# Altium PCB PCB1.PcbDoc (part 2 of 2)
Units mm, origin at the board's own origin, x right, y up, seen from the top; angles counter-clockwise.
Board outline 125 x 85 mm, 2 copper layers (Top Layer, Bottom Layer), stack 1.671 mm thick; 127 components, 99 nets, 530 pads, 139 vias.

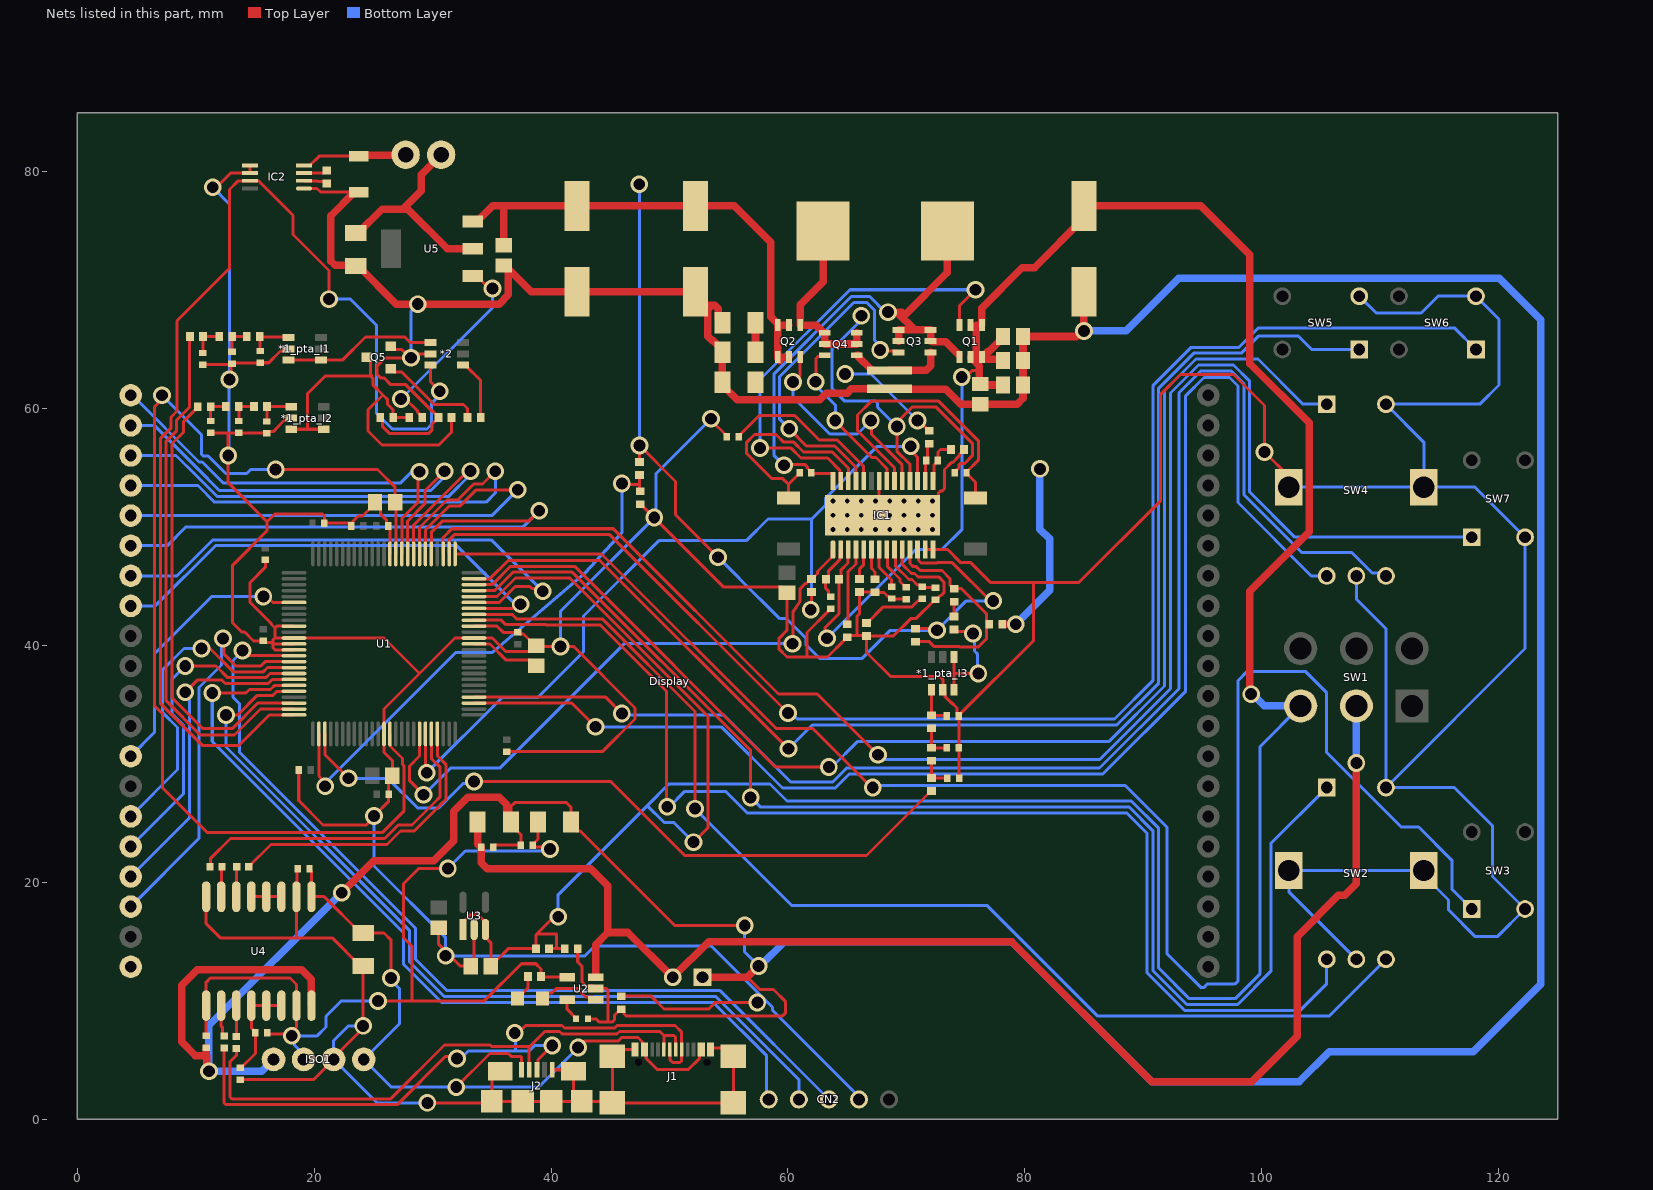
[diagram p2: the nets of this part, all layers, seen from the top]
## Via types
v1: diameter 1.5, hole 1, Top Layer to Bottom Layer, 111 vias
v2: diameter 0.5, hole 0.4, Top Layer to Bottom Layer, 12 vias
v3: diameter 0.5, hole 0.4, Top Layer to Bottom Layer, tented top, 6 vias
v4: diameter 0.5, hole 0.4, Top Layer to Bottom Layer, tented both sides, 6 vias
v5: diameter 3.5, hole 3, Top Layer to Bottom Layer, 4 vias

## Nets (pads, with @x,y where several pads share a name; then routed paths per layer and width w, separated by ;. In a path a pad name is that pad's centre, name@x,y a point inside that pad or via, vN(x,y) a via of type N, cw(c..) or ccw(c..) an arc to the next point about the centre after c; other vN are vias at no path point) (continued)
GND: *1_pta_I1.2 *1_pta_I2.2 *1_pta_I3.2 C1.1 C2.1 C3.1 C4.1 C5.1 C6.1 C7.1 C8.1 C9.1 C10.1 C11.1 C12.1 C27.2 C30.1 C31.1 C34.1 C35.1 C36.2 C37.1 C38.1 C39_pta_I1.1 C39_pta_I2.1 C39_pta_I3.1 C40_pta_I1.1 C40_pta_I2.1 C40_pta_I3.1 C41_pta_I1.1 C41_pta_I2.1 C41_pta_I3.1 CN2.4 Display.21 IC1.10 IC1.13 IC1.14 IC2.5 IC2.6 R8.1 R10.1 R14.1 R18.1 R19.2 R30.1 SW2.2 SW2.4 SW2.6 SW2.7 SW3.3 SW4.2 SW4.4 SW4.6 SW4.7 SW5.3 SW6.3 SW7.3 U1.10 U1.12 U1.13 U1.14 U1.38 U1.64 U1.66 U1.87 U3.2 | length 576.4
  Top Layer w0.254: C39_pta_I1.1@10.575,63.7 10.625,63.75 C40_pta_I1.1@13,63.75 ; C39_pta_I2.1@11.249,57.963 12.73,57.963 ; v1(11.425,78.697) 11.744,78.697 12.944,79.897 IC2.6@14.577,79.897 IC2.5@14.577,80.547 ; v1(12.85,62.465) 12.95,62.565 12.95,63.7 C40_pta_I1.1@13,63.75 ; C8.1@15.867,47.228 15.867,46.599 14.579,45.311 14.579,43.649 16.393,41.836 16.393,41.779 16.684,41.488 ; *1_pta_I1.2@17.814,65.05 17.641,64.877 17.153,64.877 16.155,63.879 15.459,63.879 C41_pta_I1.1@15.454,63.875 15.417,63.838 13.088,63.838 C40_pta_I1.1@13.05,63.8 C40_pta_I1.1@13,63.75 ; *1_pta_I2.2@18.05,59.214 17.877,59.041 17.488,59.041 16.739,58.291 16.739,58.263 16.535,58.059 16.122,58.059 C41_pta_I2.1@15.979,57.916 15.956,57.94 13.649,57.94 C40_pta_I2.1@13.625,57.963 12.73,57.963 ; U1.14@18.289,39.636 16.684,39.636 16.535,39.785 16.535,40.136 ; U1.13@18.289,40.136 16.535,40.136 ; U1.10@18.289,41.636 16.832,41.636 16.684,41.488 ; C6.1@18.689,29.487 18.689,26.907 20.745,24.852 24.393,24.852 25.039,25.497 v1(25.039,25.595) 26.283,26.839 C7.1@26.283,27.436 26.283,28.694 C1.1@26.589,29 26.589,30.286 25.889,30.986 U1.38@25.889,32.536 25.889,34.643 28.886,37.639 ; C10.1@23.122,50.092 C10.1@23.122,50.342 ; C2.1@26.239,50.092 26.116,50.215 26.116,50.59 25.609,51.097 25.609,51.635 C12.1@25.136,52.108 25.136,52.008 24.067,50.938 23.718,50.938 C10.1@23.122,50.342 ; C2.1@26.29,50.092 26.38,50.092 26.38,48.658 26.389,48.649 U1.87@26.389,47.736 ; C38.1@30.5,16.165 30.5,14.776 v1@31.428,13.848 ; v1(31.095,13.796) 31.375,13.796 v1@31.428,13.848 ; U1.66@33.489,41.636 35.437,41.637 35.957,41.117 C5.1@37.176,41.117 ; U3.2@33.5,16.015 33.5,13.216 C37.1@33.205,12.921 32.355,12.921 v1@31.428,13.848 ; C3.1@36.243,31.03 44.319,31.03 47.093,33.804 47.093,34.731 41.897,39.927 v1(40.8,39.927) C11.1@38.812,39.927 ; C5.1@37.275,41.068 37.369,40.974 37.665,40.974 C11.1@38.652,39.987 ; C11.1@38.752,39.987 C11.1@38.652,39.987 ; R19.2@45.923,10.384 48.457,10.384 49.528,9.313 53.319,9.313 53.856,9.849 v1(57.418,9.849) ; R30.1@47.524,51.933 47.574,51.933 v1(48.706,50.8) 54.583,44.923 59.444,44.923 C36.2@59.917,44.45 59.917,41.283 59.256,40.621 59.256,39.685 59.918,39.022 61.61,39.022 ; v1(53.51,59.153) 53.51,59.03 54.845,57.696 C31.1@54.845,57.646 ; C27.2@63.6,43.106 63.55,43.106 63.407,42.963 63.407,42.9 61.61,41.103 61.61,39.022 ; IC1.10@69.65,48.1 69.65,46.862 70.433,46.079 70.695,46.079 70.974,45.8 72.725,45.8 73.164,45.361 73.164,44.449 72.941,44.225 72.862,44.225 72.513,43.876 C35.1@72.463,43.876 72.413,43.876 70.804,42.267 70.367,42.267 68.9,40.8 R18.1@66.638,40.8 ; C30.1@69.993,43.92 69.965,43.948 68.791,43.948 C34.1@68.763,43.975 68.62,44.118 68.473,44.118 68.116,44.475 67.385,44.475 R10.1@67.36,44.5 67.348,44.513 66.069,44.513 R14.1@66.056,44.525 66.056,42.692 65.849,42.485 65.849,40.85 ; IC1.13@71.6,48.1 IC1.14@72.25,48.1 73.493,48.1 74.593,47 75.435,47 77.093,45.342 80.749,45.342 ; C41_pta_I3.1@74.425,34.05 C40_pta_I3.1@74.425,31.366 74.438,31.353 74.438,28.805 C39_pta_I3.1@74.451,28.791 ; SW4.6@101.277,51.954 102.3,52.977 SW4.6@102.3,53.377 102.3,54.302 v1(100.251,56.351) 100.251,60.267 97.623,62.895 93.143,62.895 91.475,61.226 91.475,52.236 84.581,45.342 80.749,45.342 ; 12.73,57.963 v1(12.73,56.05) 12.73,53.743 16.011,50.462 ; 16.011,50.462 16.011,49.684 13.111,46.783 13.111,41.898 13.866,41.142 14.117,41.142 14.873,40.387 C4.1@15.704,40.387 15.847,40.244 16.376,40.244 16.483,40.136 16.535,40.136 ; 16.011,50.462 16.651,51.102 20.7,51.102 20.849,50.953 C9.1@20.849,50.342 C10.1@23.122,50.342 ; 16.535,40.136 16.535,40.488 16.684,40.636 ; 16.684,40.636 U1.12@18.289,40.636 25.889,40.636 28.886,37.639 ; 16.684,40.636 16.684,41.488 ; 28.886,37.639 31.883,40.636 U1.64@33.489,40.636 35.036,40.636 36.194,39.478 38.144,39.478 C11.1@38.652,39.987 ; 61.61,39.022 63.347,39.022 64.765,40.44 64.765,40.49 64.836,40.561 64.886,40.561 R8.1@65.013,40.688 65.175,40.85 65.849,40.85 ; 65.849,40.85 66.588,40.85 R18.1@66.638,40.8 ; R18.1@66.638,40.8 66.638,39.415 68.655,37.398 72.818,37.398 73.075,37.142 *1_pta_I3.2@73.075,36.266 73.248,36.093 73.248,35.705 73.828,35.125 73.878,35.125 74.282,34.721 74.282,34.193 C41_pta_I3.1@74.425,34.05 74.425,34.1 80.749,40.424 80.749,45.342
  Bottom Layer w0.254: v1(11.425,78.697) 12.85,77.272 v1(12.85,62.465) 12.79,62.405 12.79,56.11 v1(12.73,56.05) ; v1(25.039,25.595) 25.039,21.377 31.095,15.321 v1(31.095,13.796) 42.859,13.796 43.683,14.62 53.526,14.62 v1@57.857,10.289 ; v1(40.8,39.927) 40.8,42.894 48.875,50.969 48.875,54.518 v1(53.51,59.153) ; v1(57.418,9.849) v1@57.857,10.289 ; CN2.4@66,1.665 66,1.906 58.695,9.211 58.695,9.451 v1@57.857,10.289 ; SW4.6@102.3,53.377 SW4.7@113.7,53.377 ; SW2.4@108,13.5 102.3,19.2 SW2.6@102.3,21 SW2.7@113.7,21 113.7,20.6 115.783,18.517 115.783,17.679 118.051,15.41 119.91,15.41 SW3.3@122.25,17.75 119.5,20.5 119.5,24.78 116.28,28 SW2.2@110.5,28 ; SW4.4@108,45.876 108,43.925 110.5,41.425 SW2.2@110.5,28 ; SW5.3@108.25,69.5 109.675,68.075 113.475,68.075 114.9,69.5 SW6.3@118.1,69.5 120.05,67.55 120.05,62 118.426,60.376 SW4.2@110.5,60.376 113.7,57.176 SW4.7@113.7,53.377 ; SW2.2@110.5,28 122.25,39.75 SW7.3@122.25,49.144 118.017,53.377 SW4.7@113.7,53.377
Net*1_pta_I1_1: *1_pta_I1.1 C41_pta_I1.2 R22_pta_I1.2 | length 3.7
  Top Layer w0.254: R22_pta_I1.2@15.404,66.1 R22_pta_I1.2@15.429,66.075 ; C41_pta_I1.2@15.454,64.875 15.429,64.9 R22_pta_I1.2@15.429,66.075 ; *1_pta_I1.1@17.814,66 17.764,66.05 15.454,66.05 R22_pta_I1.2@15.429,66.075
Net*1_pta_I1_3: *1_pta_I1.3 *1_pta_I1.4 *2.1 | length 13
  Top Layer w0.254: *1_pta_I1.3@17.814,64.1 *1_pta_I1.4@20.564,64.1 22.372,64.1 24.328,66.056 27.64,66.056 28.121,65.575 *2.1@29.804,65.575
Net*1_pta_I2_1: *1_pta_I2.1 C41_pta_I2.2 R22_pta_I2.2 | length 3.3
  Top Layer w0.254: C41_pta_I2.2@15.979,58.916 15.992,58.929 15.992,60.165 R22_pta_I2.2@16.004,60.177 16.011,60.17 18.043,60.17 *1_pta_I2.1@18.05,60.164
Net*1_pta_I2_3: *1_pta_I2.3 *1_pta_I2.4 Q5.3 R31.1 R32.2 R33.2 | length 32
  Top Layer w0.254: *1_pta_I2.3@18.05,58.263 19.425,58.263 ; *1_pta_I2.4@20.8,58.263 19.425,58.263 ; Q5.3@24.445,64.325 24.495,64.325 24.768,64.052 24.768,62.881 24.819,62.83 24.819,62.69 24.939,62.571 24.939,62.025 25.801,61.162 ; 24.819,62.765 20.925,62.765 19.425,61.265 19.425,58.263 ; R31.1@28.025,59.264 R32.2@26.664,59.264 26.664,59.887 26.199,60.351 26.199,60.764 25.801,61.162 ; R33.2@31.586,59.264 31.586,58 30.511,56.925 25.725,56.925 24.539,58.112 24.539,59.9 25.801,61.162
Net*1_pta_I3_1: *1_pta_I3.1 C41_pta_I3.2 R22_pta_I3.2 | length 3.5
  Top Layer w0.254: *1_pta_I3.1@72.125,36.266 R22_pta_I3.2@72.125,34.111 72.156,34.081 73.394,34.081 C41_pta_I3.2@73.425,34.05
Net*1_pta_I3_3: *1_pta_I3.3 *1_pta_I3.4 R16.2 | length 10.1
  Top Layer w0.254: R16.2@74.016,41.35 74.179,41.188 75.458,41.188 v1(75.62,41.025) ; *1_pta_I3.3@74.025,36.266 74.025,37.641 ; *1_pta_I3.4@74.025,39.016 74.025,37.641 ; v1(76.08,37.641) 74.025,37.641
  Bottom Layer w0.254: v1(75.62,41.025) 75.75,40.895 75.75,39.544 75.994,39.3 75.994,37.728 v1(76.08,37.641)
Net*2_3: *2.3 IC2.7 U1.25 | length 98.2
  Top Layer w0.254: U1.25@18.289,34.128 16.201,34.128 13.646,31.573 10.55,31.573 7,35.123 7,57.466 7.882,58.348 7.882,59.264 8.416,59.798 8.416,67.416 12.85,71.85 12.85,78.51 13.549,79.209 14.539,79.209 IC2.7@14.577,79.247 15.288,79.247 18.203,76.332 18.203,74.71 21.239,71.674 v1(21.239,69.25) ; *2.3@29.804,63.675 29.804,62.289 30.539,61.554 30.539,61.529 v1(30.591,61.477)
  Bottom Layer w0.254: v1(21.239,69.25) 23.05,69.25 25.239,67.061 25.239,59.639 26.586,58.291 29.526,58.291 29.913,58.678 29.913,60.462 30.539,61.088 30.539,61.425 v1(30.591,61.477)
Net*2_4: *2.4 R34.2 | length 5.1
  Top Layer w0.254: *2.4@32.554,63.675 32.754,63.675 34.047,62.381 R34.2@34.047,59.264
NetC11_2: C11.2 U1.63 | length 6
  Top Layer w0.254: U1.63@33.489,40.136 34.835,40.136 36.212,38.759 38.279,38.759 C11.2@38.752,38.286
NetC12_2: C12.2 U1.39 U1.86 | length 93.2
  Top Layer w0.254: v1(7.136,61.13) 7.136,60.794 6.505,60.162 6.505,34.918 7.2,34.223 7.2,27.969 10.974,24.195 25.739,24.195 27.557,26.013 27.557,29.853 27.455,29.955 27.455,30.464 26.398,31.52 26.398,32.528 U1.39@26.389,32.536 ; v1(16.739,54.862) 25.345,54.862 26.836,53.371 C12.2@26.836,52.108 26.889,52.055 U1.86@26.889,47.736
  Bottom Layer w0.254: v1(7.136,61.13) 10.474,57.793 10.474,56.149 10.623,56 11.036,56 12.518,54.518 14.288,54.518 14.632,54.862 v1(16.739,54.862)
NetC13_2: C13.2 C14.2 C45.2 C46.2 ISO1.3 R1.2 U2.4 U4.9 U4.15 | length 76.2
  Top Layer w0.254: C45.2@10.872,7.045 U4.9@10.872,9.59 10.872,11.567 11.222,11.917 17.943,11.917 18.492,11.369 U4.15@18.492,9.59 18.492,7.776 18.099,7.382 v1(18.099,7.045) 17.966,7.178 16.165,7.178 C46.2@16.032,7.311 ; v1(25.383,9.99) 28.239,9.99 ; v1(31.281,21.17) 31.261,21.15 28.8,21.15 27.539,19.89 27.539,15.332 28.239,14.632 28.239,9.99 ; C13.2@38.9,25.095 38.9,23.645 38.45,23.195 C14.2@38.45,23.145 38.45,23.128 38.593,22.985 39.74,22.985 v1(39.9,22.825) ; U2.4@41.354,11.981 41.327,12.008 39.179,12.008 R1.2@39.152,12.035 39.152,12.681 38.708,13.126 37.494,13.126 34.358,9.99 28.239,9.99
  Bottom Layer w0.254: ISO1.3@19.099,5.045 19.099,5.475 18.337,6.236 18.337,6.807 v1(18.099,7.045) 20.25,7.045 20.995,7.79 20.995,8.687 22.298,9.99 v1(25.383,9.99) ; v1(31.281,21.17) 32.761,22.65 39.725,22.65 v1(39.9,22.825)
NetC15_2: C15.2 C16.2 P1.2 SW1.2 U2.3 | length 121
  Top Layer w0.635: C15.2@33.8,25.095 33.8,23.225 34.055,22.97 C16.2@34.1,22.97 34.1,21.655 34.592,21.164 43.33,21.164 44.8,19.694 44.8,15.765 ; U2.3@43.754,11.981 43.754,14.719 44.8,15.765 ; v1(108,30.075) 108,19.89 107.01,18.9 106.49,18.9 103,15.41 103,7 99.165,3.165 90.714,3.165 78.879,15 53.294,15 P1.2@50.275,11.981 46.491,15.765 44.8,15.765
  Bottom Layer w0.635: v1(108,30.075) SW1.2@108,34.903
NetC17_1: C17.1 C23.2 C24.2 C25.2 C26.2 C37.2 IC1.3 Q1.2 R3.1 R3.2 R4.2 R6.2 SW1.3 U1.71 U3.1 U3.3 | length 292.5
  Top Layer w0.254: U3.1@32.55,16.015 32.55,16.611 32.813,16.874 32.813,16.896 33.215,17.298 33.785,17.298 34.45,16.633 U3.3@34.45,16.015 34.45,15.356 34.905,14.901 C37.2@34.905,13.021 ; U1.71@33.414,44.136 35.423,44.136 36.985,45.699 41.577,45.699 53.263,34.012 53.263,24.634 v1(52.025,23.395) ; C37.2@34.905,12.921 C37.2@34.905,13.021 ; R3.1@39.827,14.396 R4.2@41.15,14.396 ; 40.45,14.396 40.45,15.64 38.803,15.64 38.727,15.565 ; v1(40.6,17.09) 40.252,17.09 38.727,15.565 ; v1(63.292,40.608) 63.144,40.756 63.144,41.521 64.31,42.688 R6.2@64.31,45.6 64.463,45.753 64.463,46.356 65.076,46.969 65.076,48.076 IC1.3@65.1,48.1 ; v1(74.683,62.671) 75.02,62.671 75.587,63.239 75.863,63.239 76.175,62.926 ; C37.2@34.905,13.021 35.378,13.494 35.478,13.494 36.38,14.396 R3.2@38.727,14.396 38.727,15.565
  Top Layer w0.635: Q1.2@75.425,64.247 75.492,64.18 75.607,64.18 76.175,63.612 76.175,62.926 76.175,62.359 76.25,62.284 C23.2@76.25,62.076 ; Q1.2@75.425,64.362 75.9,64.362 ; C23.2@76.25,62 C24.2@78.15,62 ; Q1.2@76.375,64.169 78.05,64.169 C25.2@78.15,64.069 ; C26.2@78.15,66.096 78.15,65.996 76.969,64.815 76.828,64.815 Q1.2@76.375,64.362 75.9,64.362 ; v1(99.118,35.892) 99,36.011 99,44.586 104.022,49.608 104.022,58.793 99,63.815 99,73 94.875,77.125 C17.1@84.999,77.125 84.999,76.075 80.846,71.922 79.796,71.922 76.375,68.501 Q1.2@76.375,67.062 75.9,67.062 75.9,64.362
  Bottom Layer w0.254: v1(40.6,17.09) 40.6,18.956 48.124,26.48 ; v1(52.025,23.395) 50.363,25.057 49.547,25.057 48.124,26.48 ; v1(63.292,40.608) 70.784,48.1 73,48.1 74.683,49.783 v1(74.683,62.671) ; SW1.3@103.3,34.903 99.875,31.478 99.875,12.285 97.77,10.18 93.894,10.18 91.307,12.767 91.307,24.563 89,26.87 59.914,26.87 58.487,28.297 49.941,28.297 48.124,26.48
  Bottom Layer w0.635: v1(99.118,35.892) 99.234,35.892 100.224,34.903 SW1.3@103.3,34.903
NetC18_1: C18.1 C19.1 C20.2 C21.2 C22.2 C47.2 IC1.12 Q2.2 R13.2 R29.2 U5.3 | length 119.9
  Top Layer w0.254: R29.2@47.474,55.493 v1(47.474,56.884) 50.499,53.859 50.499,51.054 v1(54.103,47.45) ; R13.2@70.76,41.422 72.442,41.422 v1(72.58,41.284) ; IC1.12@70.95,48.1 71.019,48.031 71.019,47.192 71.242,46.969 72.608,46.969 72.639,47 73.875,47 77.103,43.772 v1(77.34,43.772)
  Top Layer w0.635: U5.3@33.386,75.8 33.736,75.8 35.061,77.125 36.1,77.125 ; C47.2@36,73.8 36,77.025 36.1,77.125 ; C21.2@57.26,64.762 C22.2@57.26,67.25 ; Q2.2@59.069,67.245 58.537,67.777 58.537,74.05 55.462,77.125 C19.1@52.199,77.125 C18.1@42.199,77.125 36.1,77.125 ; Q2.2@59.137,64.247 Q2.2@59.137,64.362 ; Q2.2@59.315,64.069 Q2.2@59.315,64.158 ; Q2.2@60.086,64.362 Q2.2@59.137,64.362 ; Q2.2@60.086,67.062 Q2.2@59.137,67.062 Q2.2@59.137,64.362
  Bottom Layer w0.254: v1(47.449,78.95) 47.461,78.938 47.461,56.897 v1(47.474,56.884) ; v1@54.15,47.403 57.636,43.917 57.665,43.917 59.313,42.269 59.87,42.269 61.518,40.621 61.518,40.064 62.662,38.92 66.27,38.92 68.634,41.284 v1(72.58,41.284) 75.067,43.772 v1(77.34,43.772)
NetC27_1: C27.1 IC1.2 R6.1 | length 4.7
  Top Layer w0.254: R6.1@63.21,45.6 R6.1@63.191,45.581 ; C27.1@63.6,44.106 63.55,44.106 63.407,44.249 63.407,44.629 63.191,44.844 R6.1@63.191,45.581 ; IC1.2@64.45,48.1 64.381,48.031 64.381,47.251 63.408,46.278 63.408,45.798 R6.1@63.191,45.581
NetC28_1: C28.1 IC1.28 L1.1 Q1.1 Q3.2 | length 46.5
  Top Layer w0.254: v1(59.665,55.223) 59.743,55.301 61.41,55.301 61.633,55.078 61.633,54.999 61.982,54.65 C28.1@61.982,54.6 ; C28.1@62.007,54.625 62.109,54.523 63.727,54.523 63.8,54.45 IC1.28@63.8,53.9
  Top Layer w0.635: Q3.2@69.347,65.712 Q3.2@69.347,66.662 70.697,66.662 ; L1.1@73.469,75 73.469,71.5 69.858,67.889 69.594,68.153 v1(68.453,68.153) 69.206,68.153 70.697,66.662 ; Q1.1@74.407,64.545 73.307,65.645 72.23,65.645 72.162,65.712 Q3.2@72.047,65.712 Q3.2@72.047,66.662 70.697,66.662
  Bottom Layer w0.254: v1(59.665,55.223) 58.811,56.077 58.811,62.919 65.356,69.465 66.904,69.465 68.216,68.153 v1(68.453,68.153)
NetC28_2: C28.2 D2.1 IC1.26 | length 19.2
  Top Layer w0.254: D2.1@60.048,52.45 60.048,53.616 ; C28.2@60.982,54.6 60.982,54.55 60.048,53.616 ; IC1.26@65.1,53.9 65.1,54.986 63.741,56.345 61.305,56.345 60.48,57.17 59.636,57.17 58.985,57.821 57.179,57.821 56.516,57.158 56.516,56.221 58.646,54.092 59.572,54.092 60.048,53.616
NetC29_1: C29.1 IC1.16 R9.1 | length 3.3
  Top Layer w0.254: IC1.16@71.6,53.9 71.6,55.559 71.798,55.758 71.798,56.897 R9.1@71.933,57.032
NetC29_2: C29.2 IC1.15 R12.1 | length 3.8
  Top Layer w0.254: IC1.15@72.25,53.9 72.314,53.964 72.314,55.223 72.663,55.572 72.663,56.323 72.89,56.55 R12.1@73.766,56.55
NetC30_2: C30.2 IC1.8 | length 3.9
  Top Layer w0.254: IC1.8@68.35,48.1 68.419,48.031 68.419,46.656 69.464,45.611 69.464,45.399 69.943,44.92 C30.2@69.993,44.92
NetC32_1: C32.1 IC1.18 L1.2 Q2.1 Q4.2 | length 46.9
  Top Layer w0.254: IC1.18@70.3,53.9 70.3,55.31 69.196,56.414 v1(69.196,58.487) 69.434,58.726 69.434,59.084 70.482,60.131 72.524,60.131 75.572,57.083 75.572,56.017 74.919,55.364 74.538,55.364 74.427,55.254 74.427,54.999 74.078,54.65 C32.1@74.078,54.6
  Top Layer w0.635: L1.2@62.969,75 62.969,70.704 61.036,68.772 Q2.1@61.036,67.062 62.374,67.062 62.932,66.504 62.932,66.48 63,66.412 Q4.2@63.115,66.412 Q4.2@63.115,65.462 Q4.2@65.815,65.462 Q4.2@65.815,66.412
  Bottom Layer w0.254: v1(66.2,67.851) 66.263,67.788 66.263,67.562 63.7,64.999 63.7,61.726 64.787,60.639 67.411,60.639 67.56,60.49 67.56,60.123 v1(69.196,58.487)
NetC32_2: C32.2 D3.1 IC1.20 | length 24.5
  Top Layer w0.254: IC1.20@69,53.9 69,55.006 65.869,58.137 65.869,59.469 67.04,60.639 72.735,60.639 76.08,57.293 76.08,55.652 75.078,54.65 C32.2@75.078,54.6 ; C32.2@75.078,54.55 75.841,53.787 D3.1@75.841,52.45
NetC33_1: C33.1 R18.2 | length 5.6
  Top Layer w0.254: R18.2@66.638,41.9 66.688,41.9 68.057,43.269 70.471,43.269 71.009,43.807 71.2,43.807 C33.1@71.343,43.95
NetC33_2: C33.2 C35.2 IC1.9 | length 5.5
  Top Layer w0.254: IC1.9@69,48.1 69.069,48.031 69.069,46.725 70.222,45.571 70.471,45.571 70.949,45.093 71.2,45.093 C33.2@71.343,44.95 ; C33.2@71.393,44.95 71.43,44.913 72.426,44.913 C35.2@72.463,44.876
NetC34_2: C34.2 IC1.7 | length 3.6
  Top Layer w0.254: IC1.7@67.7,48.1 67.706,48.094 67.706,46.582 68.763,45.524 C34.2@68.763,44.975
NetC39_pta_I1_2: C39_pta_I1.2 R20_pta_I1.2 R21_pta_I1.1 | length 2.8
  Top Layer w0.254: C39_pta_I1.2@10.575,64.7 10.587,64.713 10.587,66.087 R20_pta_I1.2@10.6,66.1 R21_pta_I1.1@11.975,66.1
NetC39_pta_I2_2: C39_pta_I2.2 R20_pta_I2.2 R21_pta_I2.1 | length 2.5
  Top Layer w0.254: C39_pta_I2.2@11.249,58.963 R20_pta_I2.2@11.249,60.164 11.256,60.17 12.518,60.17 R21_pta_I2.1@12.525,60.177
NetC39_pta_I3_2: C39_pta_I3.2 R20_pta_I3.2 R21_pta_I3.1 | length 2.8
  Top Layer w0.254: R20_pta_I3.2@72.125,28.816 R21_pta_I3.1@72.125,30.266 ; R20_pta_I3.2@72.125,28.816 72.138,28.804 73.439,28.804 C39_pta_I3.2@73.451,28.791
NetC40_pta_I1_2: C40_pta_I1.2 R21_pta_I1.2 R22_pta_I1.1 | length 2.5
  Top Layer w0.254: C40_pta_I1.2@13.05,64.8 13.063,64.813 13.063,66.087 R21_pta_I1.2@13.075,66.1 R22_pta_I1.1@14.304,66.1
NetC40_pta_I2_2: C40_pta_I2.2 R21_pta_I2.2 R22_pta_I2.1 | length 2.5
  Top Layer w0.254: C40_pta_I2.2@13.625,58.963 R21_pta_I2.2@13.625,60.177 R22_pta_I2.1@14.904,60.177
NetC40_pta_I3_2: C40_pta_I3.2 R21_pta_I3.2 R22_pta_I3.1 | length 2.9
  Top Layer w0.254: R22_pta_I3.1@72.125,33.011 R21_pta_I3.2@72.125,31.366 C40_pta_I3.2@73.425,31.366
NetC42_1: C42.1 C43.1 C44.2 ISO1.2 J1.1 J1.2 J1.3 J1.4 J1.A1-B12 J1.B1-A12 J2.5 J2.6 J2.7 J2.8 J2.9 J2.10 J2.11 U4.2 U4.8 | length 100.1
  Top Layer w0.254: U4.8@10.872,18.79 10.872,16.512 12.069,15.315 18.492,15.315 ; C44.2@13.762,3.333 19.926,3.333 ISO1.2@21.639,5.045 ; C43.1@18.596,21.164 18.544,21.112 18.544,18.842 U4.2@18.492,18.79 18.492,15.315 ; ISO1.2@21.552,5.132 24.127,7.707 v1(24.127,7.881) C42.1@24.127,12.921 23.902,12.921 21.508,15.315 18.492,15.315 ; v1(29.55,1.379) 34.879,1.379 J2.8@35,1.5 ; J2.6@35.673,4.05 35,3.377 J2.8@35,1.5 ; J2.5@40.1,4.175 41.775,4.175 J2.7@41.9,4.05 41.9,2.2 J2.9@42.6,1.5 ; J1.A1-B12@47.075,5.884 45.74,5.884 J1.1@45.165,5.309 J1.3@45.165,1.379 ; J1.B1-A12@53.475,5.884 53.62,6.029 54.665,6.029 J1.2@55.385,5.309 J1.4@55.385,1.379 J1.3@45.165,1.379 ; J2.8@35,1.5 J2.9@42.6,1.5 ; J2.9@42.6,1.5 45.044,1.5 J1.3@45.165,1.379
  Bottom Layer w0.254: v1(24.127,7.881) 22.881,7.881 21.639,6.639 ISO1.2@21.639,5.045 25.305,1.379 v1(29.55,1.379)
NetC42_2: C42.2 C43.2 ISO1.1 J1.A4-B9 J1.B4-A9 J2.1 U4.1 | length 63.9
  Top Layer w0.254: C43.2@19.596,21.164 19.596,21.114 19.762,20.947 U4.1@19.762,18.79 20.833,18.79 C42.2@23.902,15.721 ; C42.2@24.127,15.721 25.888,15.721 26.489,15.12 v1(26.489,11.917) ; v1(31.995,2.704) 31.995,2.716 34.832,5.553 36.38,5.553 36.624,5.309 37.401,5.309 37.479,5.231 37.479,4.196 J2.1@37.5,4.175 ; v1(42.285,6.057) 42.836,6.608 45.673,6.608 45.955,6.89 47.339,6.89 47.702,6.527 47.702,6.057 J1.A4-B9@47.875,5.884 48.007,5.752 48.007,5.156 48.983,4.18 51.567,4.18 52.543,5.156 52.543,5.752 J1.B4-A9@52.675,5.884
  Bottom Layer w0.254: v1(26.489,11.917) 26.489,11.718 27.189,11.018 27.189,8.055 ISO1.1@24.179,5.045 26.52,2.704 v1(31.995,2.704) 38.932,2.704 v1(42.285,6.057)
NetC44_1: C44.1 C46.1 U4.12 U4.13 U4.14 | length 8.5
  Top Layer w0.254: C44.1@13.762,4.333 13.812,4.333 15.032,5.553 15.032,7.361 14.682,7.711 U4.12@14.682,9.59 U4.13@15.952,9.59 U4.14@17.222,9.59
NetC48_2: C48.2 CN1.1 U5.2 | length 18
  Top Layer w0.635: C48.2@23.495,74.85 23.72,74.85 25.72,76.85 27.475,76.85 ; CN1.1@30.713,81.447 29.032,79.765 29.032,78.407 27.475,76.85 ; U5.2@33.386,73.5 31.25,73.5 27.9,76.85 27.475,76.85
NetCN1_2: CN1.2 IC2.4 R27.1 | length 9
  Top Layer w0.254: IC2.4@19.127,80.547 19.637,80.547 20.412,81.322 R27.1@23.758,81.322
  Top Layer w0.635: R27.1@23.758,81.322 23.821,81.384 27.651,81.384 CN1.2@27.713,81.447
NetCN2_1: CN2.1 U1.20 | length 74.4
  Top Layer w0.254: v1(11.384,35.986) 14.22,35.986 14.522,36.289 16.309,36.289 16.656,36.636 U1.20@18.281,36.636
  Bottom Layer w0.254: v1(11.384,35.986) 11.384,31.895 27.518,15.761 27.518,13.108 30.792,9.834 53.716,9.834 58.2,5.35 58.2,1.845 CN2.1@58.38,1.665
NetCN2_2: CN2.2 U1.21 | length 72.5
  Top Layer w0.254: v1(12.55,34.128) 13.527,34.128 15.192,35.793 16.514,35.793 16.857,36.136 U1.21@18.289,36.136
  Bottom Layer w0.254: v1(12.55,34.128) 12.55,31.429 28.026,15.953 28.026,13.318 31.002,10.342 53.926,10.342 60.92,3.348 CN2.2@60.92,1.665
NetCN2_3: CN2.3 U1.15 | length 77.1
  Top Layer w0.254: v1(13.945,39.586) 14.39,39.141 18.284,39.141 U1.15@18.289,39.136
  Bottom Layer w0.254: v1(13.945,39.586) 13.945,39.552 13.137,38.744 13.137,35.637 13.668,35.106 13.668,31.011 28.534,16.146 28.534,13.529 31.213,10.85 54.275,10.85 CN2.3@63.46,1.665
NetDisplay_23: Display.23 U1.16 | length 33.7
  Top Layer w0.254: v1(12.292,40.594) 12.389,40.497 12.389,39.251 13.371,38.27 15.488,38.27 15.854,38.636 U1.16@18.289,38.636
  Bottom Layer w0.254: Display.23@4.5,17.95 10.266,23.716 10.266,36.45 12.17,38.354 12.17,40.472 v1(12.292,40.594)
NetDisplay_24: Display.24 U1.19 | length 27.6
  Top Layer w0.254: v1(9.109,36.053) 10.161,37.105 12.164,37.105 12.485,36.784 16.103,36.784 16.456,37.136 U1.19@18.289,37.136
  Bottom Layer w0.254: Display.24@4.5,20.49 9.444,25.434 9.444,35.381 9.109,35.716 v1(9.109,36.053)
NetDisplay_25: Display.25 U1.18 | length 27.7
  Top Layer w0.254: v1(9.109,38.27) 11.699,38.27 12.69,37.279 15.898,37.279 16.255,37.636 U1.18@18.289,37.636
  Bottom Layer w0.254: Display.25@4.5,23.03 8.949,27.479 8.949,33.275 7.991,34.233 7.991,37.152 v1(9.109,38.27)
NetDisplay_26: Display.26 U1.17 | length 27.3
  Top Layer w0.254: v1(10.474,39.743) 11.198,39.743 13.166,37.775 15.693,37.775 16.055,38.136 U1.17@18.289,38.136
  Bottom Layer w0.254: Display.26@4.5,25.57 8.453,29.523 8.453,33.07 7.203,34.32 7.203,37.946 9,39.743 v1(10.474,39.743)
NetDisplay_28: Display.28 U1.6 | length 23.5
  Top Layer w0.254: v1(15.698,44.136) 16.011,44.136 16.511,43.637 U1.6@18.289,43.636
  Bottom Layer w0.254: Display.28@4.5,30.65 4.5,30.654 6.492,32.646 6.492,39.288 11.341,44.136 v1(15.698,44.136)
NetDisplay_33: Display.33 U1.69 | length 41.2
  Top Layer w0.254: U1.69@33.489,43.136 36.739,43.136 37.089,43.487 v1(37.426,43.487)
  Bottom Layer w0.254: Display.33@4.5,43.35 6.57,43.35 11.65,48.43 32.033,48.43 36.976,43.487 v1(37.426,43.487)
NetDisplay_34: Display.34 U1.70 | length 44.4
  Top Layer w0.254: U1.70@33.489,43.636 35.624,43.637 36.974,44.986 38.201,44.986 38.369,44.819 39.05,44.819 v1(39.289,44.58)
  Bottom Layer w0.254: Display.34@4.5,45.89 8.41,45.89 11.445,48.925 34.944,48.925 v1(39.289,44.58)
NetDisplay_35: Display.35 U1.80 | length 47.4
  Top Layer w0.254: U1.80@29.889,47.736 29.889,49.574 30.841,50.527 38.144,50.527 v1(39,51.383)
  Bottom Layer w0.254: Display.35@4.5,48.43 7.583,48.43 9.175,50.022 37.64,50.022 v1(39,51.383)
NetDisplay_36: Display.36 U1.81 | length 44.8
  Top Layer w0.254: U1.81@29.389,47.736 29.389,49.774 31.41,51.796 32.327,51.796 33.681,53.15 v1(37.176,53.15)
  Bottom Layer w0.254: Display.36@4.5,50.97 34.996,50.97 v1(37.176,53.15)
NetDisplay_37: Display.37 U1.82 | length 44.1
  Top Layer w0.254: U1.82@28.889,47.736 28.889,49.975 31.205,52.291 32.122,52.291 33.476,53.646 34.206,53.646 v1(35.278,54.718)
  Bottom Layer w0.254: Display.37@4.5,53.51 10.172,53.51 11.574,52.108 34.516,52.108 35.303,52.895 35.303,54.693 v1(35.278,54.718)
NetDisplay_38: Display.38 U1.83 | length 40.3
  Top Layer w0.254: U1.83@28.389,47.736 28.389,50.175 32.938,54.725 v1(33.182,54.725)
  Bottom Layer w0.254: Display.38@4.5,56.05 8.323,56.05 10.046,54.326 10.056,54.326 11.779,52.603 31.359,52.603 33.197,54.441 33.197,54.709 v1(33.182,54.725)
NetDisplay_39: Display.39 U1.84 | length 38
  Top Layer w0.254: U1.84@27.889,47.736 27.889,50.525 29.33,51.966 29.33,53.053 v1(30.995,54.718)
  Bottom Layer w0.254: Display.39@4.5,58.59 6.483,58.59 10.064,55.009 10.073,55.009 11.984,53.098 29.841,53.098 30.811,54.068 30.811,54.534 v1(30.995,54.718)
NetDisplay_40: Display.40 U1.85 | length 35.6
  Top Layer w0.254: U1.85@27.389,47.736 27.389,50.725 28.739,52.075 28.739,54.518 v1(28.889,54.668)
  Bottom Layer w0.254: Display.40@4.5,61.13 4.643,61.13 10.269,55.505 10.539,55.505 12.3,53.743 27.306,53.743 28.53,54.967 28.59,54.967 v1(28.889,54.668)
NetIC1_1: IC1.1 R7.2 U1.44 | length 51.9
  Top Layer w0.254: U1.44@28.889,32.611 28.889,30.667 28.052,29.831 28.052,28.575 v1(29.226,27.401) ; v1(60.387,40.153) 60.425,40.192 60.425,42.824 60.998,43.692 60.998,44.762 61.467,45.231 61.556,45.231 61.95,45.625 62.05,45.625 62.504,46.079 62.504,46.254 63.727,47.477 63.727,48.027 IC1.1@63.8,48.1
  Bottom Layer w0.254: v1(29.226,27.401) 29.262,27.401 29.267,27.397 31.51,29.64 35.664,29.64 46.178,40.153 v1(60.387,40.153)
NetIC1_4: IC1.4 R8.2 | length 6.6
  Top Layer w0.254: R8.2@65.013,41.788 65.06,41.836 65.06,46.2 65.75,46.889 IC1.4@65.75,48.1
NetIC1_5: IC1.5 R14.2 | length 2.6
  Top Layer w0.254: R14.2@66.056,45.625 66.058,45.627 66.058,46.479 66.4,46.821 IC1.5@66.4,48.1
NetIC1_6: IC1.6 R10.2 | length 2.6
  Top Layer w0.254: IC1.6@67.05,48.1 67.05,46.519 67.36,46.209 R10.2@67.36,45.6
NetIC1_11: IC1.11 R13.1 R15.1 R17.2 | length 18.5
  Top Layer w0.254: IC1.11@70.3,48.1 70.3,46.93 70.574,46.656 70.837,46.656 71.166,46.327 73.012,46.327 73.672,45.667 73.672,45.119 73.991,44.8 R15.1@74.041,44.8 74.649,44.8 76.751,42.698 R17.2@76.751,41.792 ; R13.1@70.76,40.321 71.943,40.321 72.367,39.897 74.483,39.897 74.486,39.894 76.089,39.894 76.751,40.557 R17.2@76.751,41.792 ; R17.2@77,41.792 R17.2@76.751,41.792
NetIC1_17: IC1.17 R7.1 U1.45 | length 69.5
  Top Layer w0.254: U1.45@29.391,31.963 29.391,29.362 v1(29.501,29.251) ; v1(61.931,43.024) R7.1@62,44.525 ; v1(70.367,56.825) 70.367,56.488 70.95,55.905 IC1.17@70.95,53.9
  Bottom Layer w0.254: v1(29.501,29.251) 35.867,35.617 38.881,35.617 42.74,39.476 42.74,42.49 49.1,48.85 56.475,48.85 58.313,50.689 62,50.689 ; v1(61.931,43.024) 62,43.093 62,50.689 ; v1(70.367,56.825) 67.551,56.825 63.182,52.456 63.182,51.87 62,50.689
NetIC1_19: IC1.19 Q2.3 | length 18.2
  Top Layer w0.254: v1(60.424,62.251) 60.487,62.251 61.036,62.8 Q2.3@61.036,64.362 ; v1(67,59) 67.041,58.959 67.041,57.869 69.65,55.26 IC1.19@69.65,53.9
  Bottom Layer w0.254: v1(60.424,62.251) 60.424,60.976 63.532,57.869 65.869,57.869 v1(67,59)
NetIC1_21: IC1.21 Q4.3 | length 13.9
  Top Layer w0.254: v1(62.341,62.276) 62.365,62.3 62.365,64.24 62.513,64.389 62.992,64.389 Q4.3@63.115,64.512 ; v1(64,59) 64,58.96 67.085,55.874 67.431,55.874 68.35,54.956 IC1.21@68.35,53.9
  Bottom Layer w0.254: v1(62.341,62.276) 62.341,61.968 64,60.309 v1(64,59)
NetIC1_25: IC1.25 Q3.3 | length 29
  Top Layer w0.254: v1(60.105,58.301) 61.553,56.853 63.951,56.853 65.75,55.054 IC1.25@65.75,53.9 ; v1(67.787,64.962) 67.864,64.885 69.224,64.885 Q3.3@69.347,64.762
  Bottom Layer w0.254: v1(60.105,58.301) 60.105,58.303 59.306,59.102 59.306,62.714 65.561,68.969 66.663,68.969 67.318,68.314 67.318,65.769 67.787,65.299 v1(67.787,64.962)
NetIC1_27: IC1.27 Q1.3 | length 39.1
  Top Layer w0.254: v1(57.647,56.69) 57.675,56.662 60.27,56.662 61.095,55.837 63.352,55.837 64.381,54.808 64.381,53.969 IC1.27@64.45,53.9 ; Q1.3@74.475,67.062 74.494,67.081 74.494,68.696 v1(75.841,70.044)
  Bottom Layer w0.254: v1(57.647,56.69) 57.647,62.457 65.235,70.044 v1(75.841,70.044)
NetIC2_2: IC2.2 R28.2 | length 2
  Top Layer w0.254: IC2.2@19.127,79.247 20.226,79.247 20.296,79.177 20.897,79.177 R28.2@21.052,79.022
NetIC2_3: IC2.3 R28.1 | length 2
  Top Layer w0.254: IC2.3@19.127,79.897 20.777,79.897 21.002,80.122 R28.1@21.052,80.122
NetJ1_A6: J1.A6 J1.B6 J2.3 R23.1 | length 58
  Top Layer w0.254: R23.1@12.389,6.012 12.389,1.374 12.538,1.225 26.997,1.225 31.068,5.296 31.886,5.296 v1(32.05,5.132) ; v1(36.925,7.278) 37.236,7.278 37.88,7.922 40.733,7.922 40.748,7.907 40.923,7.907 41.13,7.701 45.364,7.701 45.571,7.907 50.459,7.907 51.025,7.341 J1.B6@51.025,5.884 51.025,4.932 50.875,4.782 50.273,4.782 50.025,5.03 J1.A6@50.025,5.884 ; J2.3@38.8,4.175 38.873,4.248 38.873,4.994 v1(40.102,6.223)
  Bottom Layer w0.254: v1(32.05,5.132) 32.387,5.132 33.007,5.752 37,5.752 ; v1(36.925,7.278) 37,7.203 37,5.752 ; v1(40.102,6.223) 38.618,6.223 38.147,5.752 37,5.752
NetJ1_A7: J1.A7 J1.B7 J2.2 R25.1 | length 49.1
  Top Layer w0.254: R25.1@13.412,5.962 13.412,5.379 12.885,4.852 12.885,1.869 13.033,1.72 26.453,1.72 31.003,6.27 34.856,6.27 34.985,6.141 38.15,6.141 J2.2@38.15,4.175 ; 38.15,6.089 39.473,7.412 40.718,7.412 40.924,7.205 45.57,7.205 45.776,7.412 49.178,7.412 49.525,7.065 ; J1.B7@49.525,5.884 49.525,7.065 ; J1.A7@50.525,5.884 50.525,6.917 50.376,7.065 49.525,7.065
NetLED1_1: LED1.1 U2.1 | length 5.4
  Top Layer w0.254: LED1.1@39.277,10.181 39.277,10.231 39.7,10.654 40.064,10.654 40.427,11.017 42.419,11.017 42.554,10.882 42.554,10.692 42.946,10.3 43.535,10.3 U2.1@43.754,10.081
NetLED1_2: LED1.2 R1.1 | length 2.2
  Top Layer w0.254: LED1.2@37.177,10.181 37.177,10.231 38.052,11.106 R1.1@38.052,12.035
NetQ3_1: Q3.1 Q4.1 R9.2 R11.2 | length 15.7
  Top Layer w0.254: v1(70.95,59) 71.016,59 71.883,58.132 R9.2@71.933,58.132
  Top Layer w0.635: Q4.1@65.815,64.512 65.93,64.512 65.997,64.445 65.997,64.33 67.014,63.312 67.014,63.259 R11.2@67.047,63.226 ; R11.2@68.597,63.226 68.609,63.239 71.675,63.239 72.047,63.611 Q3.1@72.047,64.762
  Bottom Layer w0.254: v1(64.831,62.934) 67.016,62.934 v1(70.95,59)
NetQ5_1: Q5.1 R34.1 | length 8.6
  Top Layer w0.254: Q5.1@26.445,63.375 26.718,63.102 27.384,63.102 30.128,60.359 32.608,60.359 32.947,60.02 R34.1@32.947,59.264
NetR2_2: R2.2 U2.5 | length 2
  Top Layer w0.254: U2.5@41.354,10.081 41.354,9.278 42.15,8.481 R2.2@42.175,8.481
NetR15_2: R15.2 R16.1 | length 1.3
  Top Layer w0.254: R16.1@74.016,42.45 74.029,42.463 74.029,43.688 R15.2@74.041,43.7
NetR20_pta_I1_1: R20_pta_I1.1 U1.24 | length 44.5
  Top Layer w0.254: R20_pta_I1.1@9.5,66.1 9.456,66.056 9.456,60.121 8.377,59.042 8.377,58.143 7.495,57.261 7.495,35.328 10.374,32.449 13.267,32.449 15.454,34.636 U1.24@18.289,34.636
NetR20_pta_I2_1: R20_pta_I2.1 U1.23 | length 37.7
  Top Layer w0.254: R20_pta_I2.1@10.149,60.164 10.149,60.114 8.971,58.935 8.971,58.036 7.991,57.056 7.991,35.589 10.57,33.01 13.109,33.01 15.236,35.136 U1.23@18.281,35.136
NetR20_pta_I3_1: R20_pta_I3.1 U1.28 | length 60.6
  Top Layer w0.254: U1.28@20.897,32.537 20.905,32.529 20.905,30.77 v1(22.889,28.786) ; v1(33.482,28.509) 45.047,28.509 51.279,22.277 66.635,22.277 72.075,27.716 R20_pta_I3.1@72.125,27.716
  Bottom Layer w0.254: v1(22.889,28.786) 26.214,28.786 28.73,26.27 30.509,26.27 32.569,28.33 33.303,28.33 v1(33.482,28.509)
NetR23_2: R23.2 U4.10 | length 2.7
  Top Layer w0.254: U4.10@12.142,9.59 12.142,7.851 12.267,7.726 12.267,7.118 R23.2@12.389,6.995
NetR24_1: R24.1 U4.7 | length 2.6
  Top Layer w0.254: U4.7@12.142,18.79 12.157,18.805 12.157,21.315 R24.1@12.172,21.33
NetR24_2: R24.2 U1.46 | length 27.9
  Top Layer w0.254: R24.2@11.222,21.33 11.222,22.005 12.917,23.7 25.944,23.7 27.096,24.852 28.258,24.852 30.105,26.698 30.105,26.707 30.632,27.235 30.632,29.72 29.889,30.464 U1.46@29.889,32.536
NetR25_2: R25.2 U4.11 | length 2.6
  Top Layer w0.254: R25.2@13.412,6.945 U4.11@13.412,9.59
NetR26_1: R26.1 U4.6 | length 2.6
  Top Layer w0.254: U4.6@13.412,18.79 13.449,18.827 13.449,21.293 R26.1@13.487,21.33
NetR26_2: R26.2 U1.47 | length 24.9
  Top Layer w0.254: R26.2@14.437,21.33 14.462,21.33 16.336,23.204 26.149,23.204 27.288,24.344 28.451,24.344 30.6,26.493 30.6,26.501 31.14,27.042 31.14,29.93 30.397,30.674 30.397,31.615 30.389,31.623 U1.47@30.389,32.536
NetR29_1: R29.1 R30.2 U1.27 | length 45.6
  Top Layer w0.254: U1.27@20.389,32.536 20.389,31.623 20.397,31.615 20.397,28.967 20.917,28.447 v1(20.917,28.11) ; v1(45.975,53.674) 46.066,53.583 47.474,53.583 ; R29.1@47.474,54.393 47.474,53.583 ; R30.2@47.524,53.033 47.474,53.082 47.474,53.583
  Bottom Layer w0.254: v1(20.917,28.11) 20.917,28.396 31.919,39.398 34.999,39.398 42.879,46.135 42.891,46.146 45.975,49.526 v1(45.975,53.674)
NetR31_2: R31.2 U5.1 | length 17.2
  Top Layer w0.254: v1(27.33,60.82) 27.376,60.866 27.662,60.866 28.731,59.796 28.731,59.707 29.125,59.314 R31.2@29.125,59.264 ; U5.1@33.386,71.2 33.736,71.2 34.786,70.15 v1(35.061,70.15)
  Bottom Layer w0.254: v1(27.33,60.82) 35.061,68.551 v1(35.061,70.15)
NetSW2_1: SW2.1 U1.72 | length 110.9
  Top Layer w0.254: U1.72@33.489,44.636 35.223,44.637 36.78,46.194 41.783,46.194 56.85,31.126 v1(56.85,27.166)
  Bottom Layer w0.254: v1(56.85,27.166) 56.867,27.166 57.658,26.375 88.795,26.375 90.812,24.358 90.812,19.948 90.812,12.562 93.689,9.685 97.975,9.685 100.782,12.492 100.782,23.282 SW2.1@105.5,28
NetSW2_3: SW2.3 U1.68 | length 97.9
  Top Layer w0.254: U1.68@33.489,42.636 33.492,42.64 36.691,42.64 37.081,42.25 44.325,42.25 52.145,34.43 v1(52.145,26.225)
  Bottom Layer w0.254: v1(52.145,26.225) 60.341,18.029 76.837,18.029 86.172,8.694 105.694,8.694 SW2.3@110.5,13.5
NetSW2_5: SW2.5 U1.67 | length 102.4
  Top Layer w0.254: U1.67@33.416,42.138 34.522,42.138 34.528,42.145 35.79,42.145 36.18,41.755 39.563,41.755 39.575,41.743 44.132,41.743 49.745,36.13 49.745,26.441 v1(49.805,26.38)
  Bottom Layer w0.254: v1(49.805,26.38) 49.989,26.38 51.295,27.686 54.731,27.686 56.563,25.854 88.615,25.854 90.316,24.153 90.316,12.357 93.484,9.189 103.261,9.189 105.5,11.428 SW2.5@105.5,13.5
NetSW3_1: SW3.1 U1.76 | length 146.9
  Top Layer w0.254: U1.76@31.897,47.736 44.263,47.736 58.988,33.011 62.068,33.011 67.078,28.001 v1(67.163,28.001)
  Bottom Layer w0.254: v1(67.163,28.001) 66.898,28.001 66.738,28.16 88.51,28.16 92,24.671 92,14 94.895,11.105 95.105,11.105 95.428,11.428 97.77,11.428 98,11.658 98,37.029 98.788,37.818 103.693,37.818 105.5,36.011 105.5,30.96 111.789,24.671 113.268,24.671 116.067,21.871 116.067,19.433 SW3.1@117.75,17.75
NetSW4_1: SW4.1 U1.73 | length 110.1
  Top Layer w0.254: U1.73@33.489,45.136 35.022,45.136 36.575,46.689 41.988,46.689 58.939,29.738 v1(63.453,29.738)
  Bottom Layer w0.254: v1(63.453,29.738) 63.724,29.738 65.897,31.911 87.131,31.911 91.802,36.583 91.802,61.526 94.465,64.189 99.691,64.189 103.504,60.376 SW4.1@105.5,60.376
NetSW4_3: SW4.3 U1.54 | length 121.7
  Top Layer w0.254: U1.54@33.489,35.636 44.606,35.636 v1(45.975,34.267)
  Bottom Layer w0.254: v1(45.975,34.267) 46.106,34.137 54.58,34.137 60.242,28.474 63.79,28.474 64.965,29.649 86.305,29.649 93.016,36.36 93.016,61.339 94.875,63.198 97.412,63.198 98.495,62.115 98.495,52.754 103.405,47.844 107.632,47.844 109.369,46.107 110.269,46.107 SW4.3@110.5,45.876
NetSW4_5: SW4.5 U1.53 | length 116.6
  Top Layer w0.254: U1.53@33.489,35.128 41.762,35.128 v1(43.754,33.136)
  Bottom Layer w0.254: v1(43.754,33.136) 54.366,33.136 59.536,27.966 64,27.966 65.175,29.141 86.591,29.141 93.591,36.141 93.591,61.089 95.127,62.625 97.285,62.625 98,61.91 98,52.074 104.198,45.876 SW4.5@105.5,45.876
NetSW5_1: SW5.1 U1.74 | length 111.5
  Top Layer w0.254: U1.74@33.489,45.636 34.822,45.637 36.37,47.184 44.115,47.184 60.019,31.28 v1(60.048,31.28)
  Bottom Layer w0.254: v1(60.048,31.28) 62.059,33.291 87.774,33.291 91.307,36.824 91.307,61.731 94.26,64.684 98.288,64.684 99.722,66.118 103.116,66.118 104.234,65 SW5.1@108.25,65
NetSW6_1: SW6.1 U1.77 | length 123.5
  Top Layer w0.254: U1.77@31.398,47.827 31.398,48.939 31.825,49.366 44.944,49.366 v1(60.01,34.3)
  Bottom Layer w0.254: v1(60.01,34.3) 60.268,34.3 60.782,33.786 87.569,33.786 90.812,37.029 90.812,61.937 94.054,65.179 98.083,65.179 99.728,66.824 116.276,66.824 SW6.1@118.1,65
NetSW7_1: SW7.1 U1.78 | length 136.7
  Top Layer w0.254: U1.78@30.889,47.736 30.889,49.13 31.619,49.861 45.253,49.861 59.202,35.912 62.472,35.912 v1(67.604,30.78)
  Bottom Layer w0.254: v1(67.604,30.78) 67.752,30.632 67.752,30.384 86.322,30.384 92.297,36.36 92.297,61.321 94.67,63.693 97.618,63.693 98.991,62.32 98.991,52.959 102.806,49.144 SW7.1@117.75,49.144
NetU4_3: U4.3 U4.4 U4.5 | length 2.5
  Top Layer w0.254: U4.5@14.682,18.79 U4.4@15.952,18.79 U4.3@17.222,18.79
PGND: *2.2 C13.1 C14.1 C15.1 C16.1 C17.2 C18.2 C19.2 C20.1 C21.1 C22.1 C23.1 C24.1 C25.1 C26.1 C45.1 C47.1 C48.1 IC1.22 IC1.- IC2.1 ISO1.4 P1.1 Q5.2 R2.1 R4.1 R11.1 R12.2 R17.1 R19.1 R27.2 R32.1 R33.1 U2.2 U4.16 | length 470.7
  Top Layer w0.254: IC2.1@19.127,78.597 20.239,78.597 20.52,78.316 23.074,78.316 23.251,78.139 23.383,78.272 R27.2@23.758,78.272 ; R32.1@25.564,59.264 25.748,59.08 25.748,58.508 26.339,57.916 29.675,57.916 29.929,58.17 29.929,58.656 30.486,59.214 R33.1@30.486,59.264 30.486,59.314 30.014,59.786 29.964,59.786 27.725,62.025 26.464,62.025 25.882,62.607 25.603,62.607 25.314,62.896 25.314,63.615 25.999,64.3 v1@28.08,64.3 ; Q5.2@26.445,65.275 26.718,65.002 27.378,65.002 v1@28.08,64.3 ; *2.2@29.804,64.625 28.562,64.625 28.237,64.3 v1(28.158,64.3) v1@28.08,64.3 ; C16.1@35.1,22.97 35.1,23.002 35.243,23.145 C14.1@37.45,23.145 37.45,24.02 36.6,24.87 C15.1@36.6,25.095 36.6,26.4 36.925,26.725 41.295,26.725 41.7,26.32 C13.1@41.7,25.095 41.7,24.87 42.248,24.322 42.473,24.322 50.43,16.365 v1(56.35,16.365) ; R4.1@42.25,14.396 42.25,13.271 42.6,12.921 42.6,11.596 42.946,11.25 43.535,11.25 U2.2@43.754,11.031 44.651,11.031 44.8,10.882 44.8,8.196 ; R2.1@43.025,8.481 43.782,8.481 44.068,8.196 44.8,8.196 ; R19.1@45.923,9.284 R19.1@45.973,9.284 ; 56.573,11.984 56.576,11.987 57.612,10.951 58.777,10.951 59.813,9.914 59.813,8.988 59.556,8.731 46.32,8.731 46.171,8.88 46.171,9.086 R19.1@45.973,9.284 ; IC1.22@67.7,53.9 67.7,51.3 IC1.-@68,51 v2(68.6,51) v2(69.8,51) v3(71,51) 71.15,51 IC1.-@72.723,52.573 ; IC1.-@72.275,52.125 IC1.-@72.723,52.573 ; R12.2@74.866,56.55 74.866,56.5 74.472,56.106 74.472,56.017 73.897,55.442 73.791,55.442 73.216,54.867 73.216,53.249 73,53.033 72.871,53.033 72.723,52.884 IC1.-@72.723,52.573 ; 44.8,8.196 45.159,8.196 45.339,8.376 45.339,8.75 45.873,9.284 R19.1@45.973,9.284
  Top Layer w0.635: C45.1@10.872,6.045 10.872,5.377 ; v1(11.101,4.05) 10.935,4.216 10.935,5.314 10.872,5.377 ; U4.16@19.762,9.59 19.762,11.801 18.947,12.616 10.116,12.616 8.817,11.317 8.817,6.52 9.96,5.377 10.872,5.377 ; v1(22.317,19.129) 25.025,21.836 30.096,21.836 31.781,23.521 31.781,26.012 32.951,27.182 35.625,27.182 36.243,26.565 36.243,25.228 C15.1@36.6,24.87 ; R27.2@23.251,78.139 21.411,76.299 21.411,72.472 21.783,72.1 23.445,72.1 C48.1@23.495,72.05 23.72,72.05 26.941,68.829 v1(28.739,68.829) 35.609,68.829 36.383,69.603 36.383,70.697 ; C47.1@36,72.1 36.1,72.1 C47.1@36.383,71.818 ; 36.383,70.698 C47.1@36.383,71.818 ; P1.1@52.775,11.981 52.778,11.984 56.573,11.984 ; C21.1@54.46,64.762 C21.1@54.46,64.537 ; C22.1@54.46,67.25 54.103,67.607 54.103,68.439 53.821,68.722 53.549,68.722 ; 56.576,11.987 v1(57.526,12.938) ; R11.1@68.597,61.676 R11.1@69.925,61.676 ; R17.1@78.1,41.792 v1(79.239,41.792) ; 84.362,66.096 C26.1@79.85,66.096 C25.1@79.85,64.069 C24.1@79.85,62 79.85,60.874 79.353,60.376 C23.1@76.25,60.376 74.593,60.376 73.318,61.651 69.988,61.651 69.944,61.696 R11.1@69.925,61.676 ; v1(85,66.562) C17.2@84.999,69.875 C17.2@84.999,69.875 ; C47.1@36.383,71.818 38.325,69.875 C18.2@42.199,69.875 C19.2@52.199,69.875 52.199,69.454 52.932,68.722 53.549,68.722 ; 53.549,68.722 53.214,68.387 53.214,66.113 53.549,65.779 53.669,65.779 54.46,64.987 C21.1@54.46,64.537 ; C21.1@54.46,64.537 C20.1@54.46,62.225 54.46,62 55.716,60.744 62.678,60.744 63.255,61.322 65.002,61.322 65.357,61.676 R11.1@69.925,61.676
  Bottom Layer w0.254: v1(28.158,64.3) 28.158,68.204 28.739,68.785 v1(28.739,68.829) ; v1(56.35,16.365) 56.35,14.114 v1(57.526,12.938)
  Bottom Layer w0.635: ISO1.4@16.559,5.045 15.564,4.05 v1(11.101,4.05) 11.101,7.912 v1(22.317,19.129) ; v1(57.526,12.938) 57.646,12.938 59.708,15 78.879,15 90.714,3.165 103.159,3.165 105.694,5.7 117.875,5.7 123.559,11.384 123.559,67.491 120.05,71 93,71 88.562,66.562 v1(85,66.562) ; v1(79.239,41.792) 82.1,44.653 82.1,49 81.275,49.825 v1(81.275,54.92)
  other v2: 66.2,49.8 67.4,49.8 68.6,49.8 69.8,49.8 66.2,51 67.4,51 66.2,52.2 67.4,52.2 68.6,52.2 69.8,52.2
  other v3: 71,49.8 72.2,49.8 72.2,51 71,52.2 72.2,52.2
  other v4: 63.8,49.8 65,49.8 63.8,51 65,51 63.8,52.2 65,52.2
V_out: C31.2 IC1.24 | length 14.3
  Top Layer w0.254: C31.2@55.845,57.646 55.845,57.696 57.581,59.432 60.573,59.432 62.644,57.361 64.162,57.361 66.4,55.123 IC1.24@66.4,53.9
pads on no net: *1_pta_I1.5 *1_pta_I2.5 *1_pta_I3.5 *2.5 Display.1 Display.2 Display.3 Display.4 Display.5 Display.6 Display.7 Display.8 Display.9 Display.10 Display.11 Display.12 Display.13 Display.14 Display.15 Display.16 Display.17 Display.18 Display.19 Display.20 Display.27 Display.29 Display.30 Display.31 Display.32 J1. J1.A5 J1.A8 J1.B5 J1.B8 J2.4 SW1.1 SW1.4 SW1.5 SW1.6 SW3.2 SW3.4 SW5.2 SW5.4 SW6.2 SW6.4 SW7.2 SW7.4 U1.1 U1.2 U1.3 U1.4 U1.5 U1.7 U1.8 U1.9 U1.11 U1.22 U1.29 U1.30 U1.31 U1.32 U1.33 U1.34 U1.35 U1.36 U1.40 U1.41 U1.42 U1.43 U1.48 U1.49 U1.51 U1.52 U1.55 U1.56 U1.57 U1.58 U1.59 U1.60 U1.61 U1.62 U1.79 U1.89 U1.90 U1.91 U1.92 U1.93 U1.94 U1.95 U1.96 U1.97 U1.98 U1.99 U3.4 U5.4
copper on no net:
  other v5: 4.28,6.52 95.72,6.52 4.28,67.48 95.72,67.48

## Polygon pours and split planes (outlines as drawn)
GND on Top Layer "GND" (solid, pour order 15): -0.05,90.025 130,90.025 130,0 0,0
PGND on Top Layer "PGND" (solid, pour order 10): 0,90.025 130,90.025 130,39.986 44,39.986 44,56.724 0,56.724
GND on Top Layer "GND" (solid, pour order 16): 54.295,-15
no net on Top Layer "PGND" (solid, pour order 9): -0.05,90.025
NetC18_1 on Top Layer "NETC18_1_L01_P008" (solid, pour order 8): 59.836,69.454 60.373,68.917 60.373,62.926 60.062,62.926 58.206,61.071 56.331,61.071 56.449,73.7 55.836,73.7 55.16,73.7 33.891,73.7 31.791,75.8 31.791,77.75 34.191,80.15 55.836,80.15 59.836,76.15
PGND on Top Layer "PGND" (solid, pour order 1): 44,62.765 57.765,49 79.162,49 90,59.838 90,72.7 83.55,72.7 79,68.15 79,62.026 56.449,62.026 56.449,63.935 56.449,73.25 29.025,73.25 25.925,76.35 25.925,79.297 23.274,79.297 20.849,76.871 20.849,67.75 25.834,62.765
NetC32_1 on Top Layer "PGND" (solid, pour order 7): 60.086,79.225 68.013,79.225 68.013,65.034 67.941,64.962 61.786,64.962 60.086,66.662 60.086,78
NetC28_1 on Top Layer "PGND" (solid, pour order 6): 73.325,68.2 73.343,68.182 73.349,66.439 74.925,64.862 74.925,63.369 74.44,63.369 72.663,65.146 68.275,65.146 68.275,68.632 68.275,79.26 76.225,79.187 76.225,71.1
NetC17_1 on Top Layer "NETC17_1_L01_P000" (solid, pour order 0): 87.649,80 87.649,73 83.433,73 78.75,68.317 79,68.067 79,61.37 75.219,61.37 75.219,69.969 80.846,75.596 80.846,80
NetQ3_1 on Top Layer "NETQ3_1_L01_P005" (solid, pour order 5): 64.465,62.451 72.05,62.451 72.797,63.198 72.797,65.012 64.465,65.012
no net on Top Layer "PGND" (solid, pour order 4): 86,74
no net on Top Layer "PGND" (solid, pour order 3): 77.55,74.5
no net on Top Layer "PGND" (solid, pour order 2): 92,27.7
GND on Bottom Layer "GND" (solid, pour order 14): -0.194,89.636 -0.194,-0.389 129.806,-0.389 129.806,89.611
PGND on Bottom Layer "PGND" (solid, pour order 12): -0.05,90.025 130,90.025 130,39.986 44,39.986 44,56.724 0,56.724
PGND on Bottom Layer "PGND" (solid, pour order 13): 165,53

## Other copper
Top Layer:
  text "-" at 27.066,78.536 h1
  text "+" at 30.161,78.432 h1
  text "Power Supply / Simen Sollihogda / rev2 / .Print_Date" at 74.483,18 h1
  text "-" at 52.145,9.834 h1
  text "+" at 49.681,9.681 h1
Bottom Layer:
  text "-" at 52.17,13.23 h1
  text "+" at 49.706,13.077 h1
